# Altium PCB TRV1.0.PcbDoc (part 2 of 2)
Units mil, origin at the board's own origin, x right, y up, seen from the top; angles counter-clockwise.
Board outline 1659.57 x 2276.55 mil, 2 copper layers (Top Layer, Bottom Layer); 70 components, 42 nets, 217 pads, 204 vias.

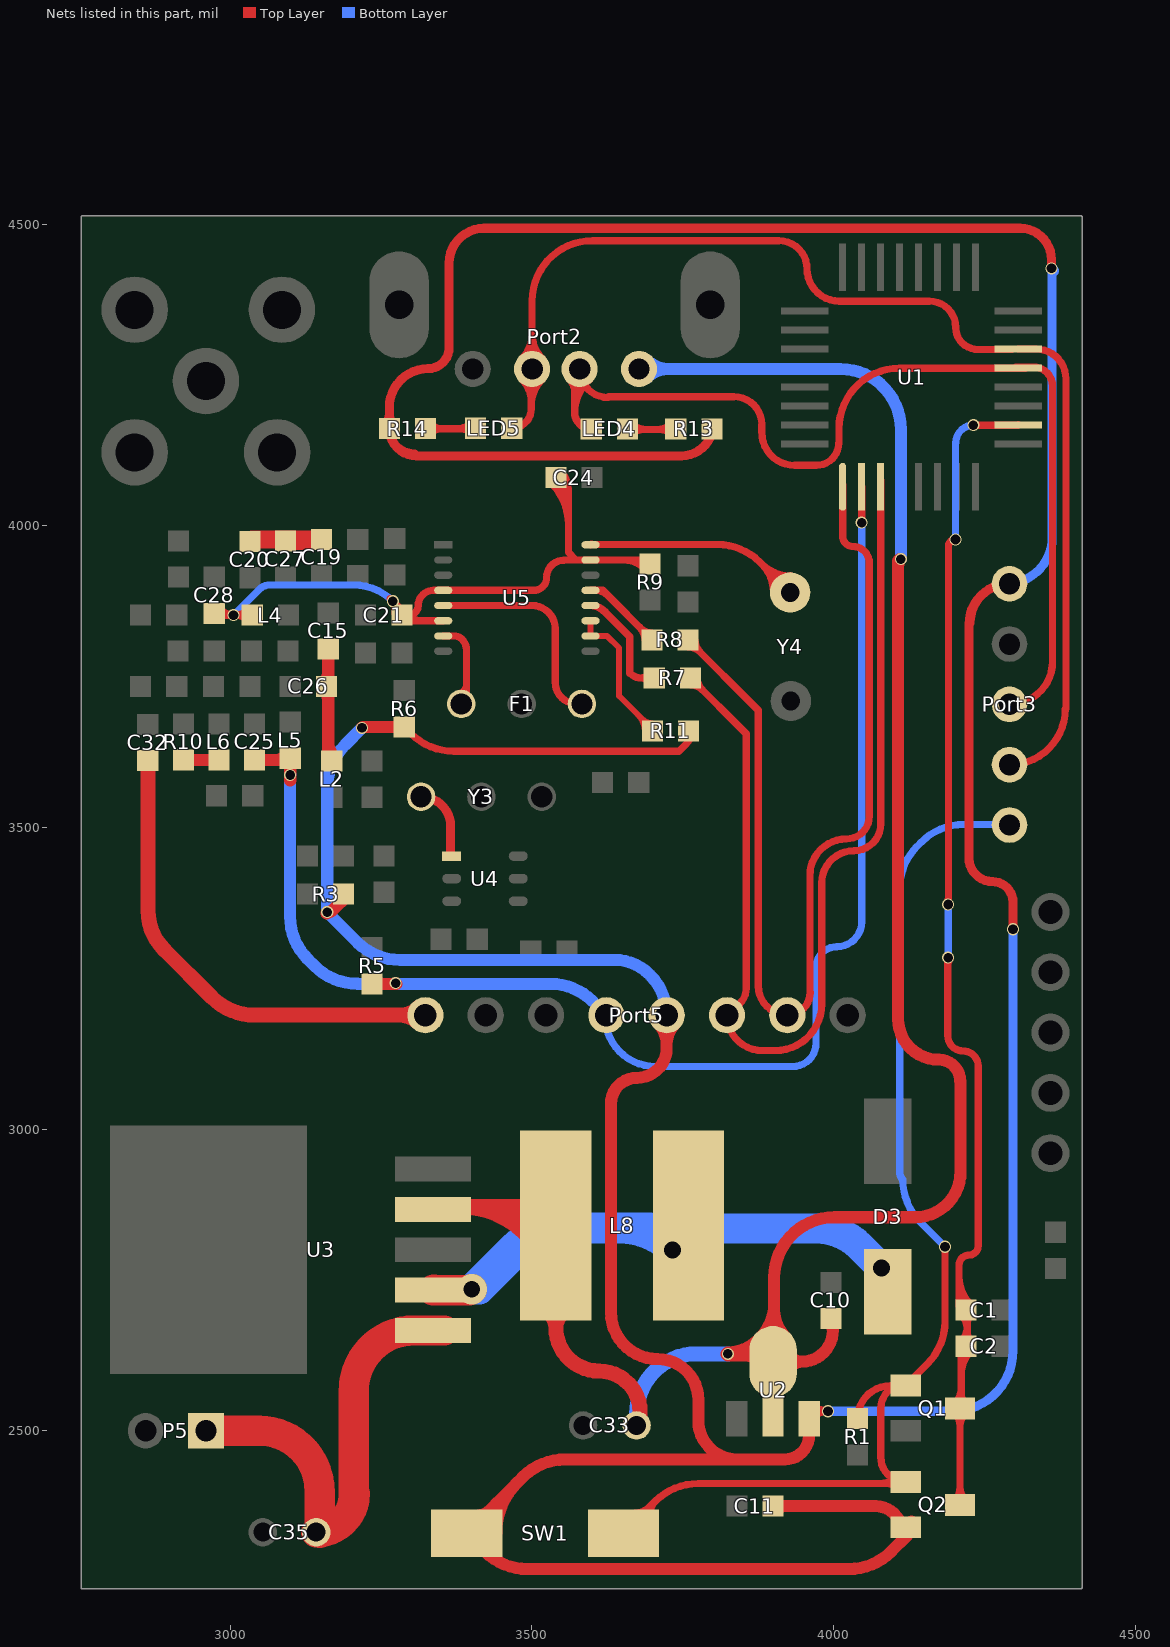
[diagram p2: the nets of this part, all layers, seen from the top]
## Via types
v1: diameter 20, hole 16, Top Layer to Bottom Layer, 201 vias
v2: diameter 50, hole 28, Top Layer to Bottom Layer, 3 vias

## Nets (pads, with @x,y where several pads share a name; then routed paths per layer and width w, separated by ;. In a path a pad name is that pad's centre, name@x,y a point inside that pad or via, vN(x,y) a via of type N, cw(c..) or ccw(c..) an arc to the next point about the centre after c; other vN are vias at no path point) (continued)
NetC32_2: C32.2 Port5.1 | length 997.3
  Top Layer w25: C32.2@2864.92,3607.21 ccw(c2859.9,3607.21) C32.2@2863.45,3610.76 cw(c2861.99,3609.3) 2864.06,3609.3 2864.06,3362.05 ccw(c2955.64,3362.05) 2890.88,3297.29 2970.09,3218.08 ccw(c3040.8,3288.79) 3040.8,3188.79 Port5.1@3323.69,3188.79 ; 3281.44,3188.79 ccw(c3281.44,3231.04) Port5.1@3311.32,3201.17 ; 3281.44,3188.79 cw(c3281.44,3146.54) Port5.1@3311.32,3176.42 ; 3281.44,3188.79 ccw(c3281.44,3231.04) Port5.1@3311.32,3201.17 ; 3281.44,3188.79 cw(c3281.44,3146.54) Port5.1@3311.32,3176.42 ; 3281.44,3188.79 ccw(c3281.44,3231.04) Port5.1@3311.32,3201.17 ; 3281.44,3188.79 cw(c3281.44,3146.54) Port5.1@3311.32,3176.42
NetC35_1: C35.1 P5.1 U3.1 | length 893.4
  Top Layer w50: P5.1@2960,2500 3048.39,2500 cw(c3048.39,2400) 3148.39,2400 cw(c3148.39,2399.87) 3148.52,2399.87 C35.1@3148.52,2332 ; C35.1@3148.52,2330.28 C35.1@3148.52,2331.99 ; 3207.04,2396.02 cw(c3142.76,2396.02) C35.1@3148.52,2331.99 ; U3.1@3354.95,2666.33 3305.08,2666.33 ccw(c3305.08,2566.33) 3205.08,2566.33 3205.08,2394.06 cw(c3142.76,2394.06) C35.1@3148.52,2332 ; C35.1@3148.52,2331.99 cw(c3142.76,2396.02) C35.1@3142.76,2331.73 ccw(c3142.76,2394.06) C35.1@3148.52,2332
NetD3_2: D3.2 L8.1 U3.2 | length 1406.9
  Top Layer w50: U3.2@3336.49,2732.96 cw(c3336.49,2733.34) U3.2@3336.22,2733.07 cw(c3338.37,2730.92) 3338.37,2733.96 ccw(c3340.8,2736.39) 3340.8,2732.96 3396.97,2732.96 cw(c3400.61,2729.32) v2(3400.61,2734.47) ; v2(3733.07,2799.49) cw(c3725.34,2791.77) L8.1@3736.27,2791.77 ; v2(3733.07,2799.49) cw(c3725.34,2791.77) L8.1@3736.27,2791.77 ; v2(3733.07,2799.49) cw(c3725.34,2791.77) L8.1@3736.27,2791.77
  Bottom Layer w50: 3647.13,2835.09 cw(c3647.13,2713.55) v2(3733.07,2799.49) ; 3819.01,2835.09 ccw(c3819.01,2713.55) v2(3733.07,2799.49) ; v2(4079.59,2769.9) 4043.69,2805.8 ccw(c3972.98,2735.09) 3972.98,2835.09 3894.69,2835.09 3544.33,2835.09 ccw(c3544.33,2831.04) 3541.47,2833.9 ccw(c3541.47,2733.9) 3470.76,2804.61 v2(3400.61,2734.47) 3413.06,2734.47 3485.81,2807.22 cw(c3556.52,2736.51) 3556.52,2836.51 3696.05,2836.51 v2(3733.07,2799.49)
NetF1_1: F1.1 U5.7 | length 203
  Top Layer w12: U5.7@3353.33,3817.41 3371.88,3817.41 cw(c3371.88,3799.96) 3384.22,3812.3 cw(c3365.71,3793.79) 3391.89,3793.79 3391.89,3736.01 ; F1.1@3383.25,3704.82 ccw(c3362.41,3725.66) 3391.89,3725.66 3391.89,3736.01 ; F1.1@3380.25,3722.18 ccw(c3377.86,3736.01) 3391.89,3736.01 ; F1.1@3380.25,3722.18 ccw(c3377.86,3736.01) 3391.89,3736.01 ; F1.1@3380.25,3722.18 ccw(c3377.86,3736.01) 3391.89,3736.01
NetF1_3: F1.3 U5.5 | length 361.1
  Top Layer w12: U5.5@3353.33,3867.81 3500.55,3867.81 cw(c3500.55,3829.39) 3538.96,3829.39 ccw(c3538.96,3829.31) 3538.88,3829.31 3538.88,3740.91 ccw(c3574.98,3740.91) 3574.98,3704.82 F1.3@3583.25,3704.82
NetL6_1: L6.1 R10.1 | length 229.7
  Top Layer w20: R10.1@2922.51,3611.71 L6.1@2981.56,3611.71 ; R10.1@2927.81,3606.4 cw(c2940.61,3593.6) 2940.61,3611.71 ; R10.1@2927.81,3606.4 cw(c2940.61,3593.6) 2940.61,3611.71 ; R10.1@2927.81,3606.4 cw(c2940.61,3593.6) 2940.61,3611.71 ; R10.1@2927.81,3617.01 ccw(c2940.61,3629.81) 2940.61,3611.71 ; R10.1@2927.81,3617.01 ccw(c2940.61,3629.81) 2940.61,3611.71 ; R10.1@2927.81,3617.01 ccw(c2940.61,3629.81) 2940.61,3611.71 ; 2963.45,3611.71 ccw(c2963.45,3629.81) L6.1@2976.26,3617.01 ; 2963.45,3611.71 cw(c2963.45,3593.6) L6.1@2976.26,3606.4 ; 2963.45,3611.71 ccw(c2963.45,3629.81) L6.1@2976.26,3617.01 ; 2963.45,3611.71 cw(c2963.45,3593.6) L6.1@2976.26,3606.4 ; 2963.45,3611.71 ccw(c2963.45,3629.81) L6.1@2976.26,3617.01 ; 2963.45,3611.71 cw(c2963.45,3593.6) L6.1@2976.26,3606.4
NetLED4_1: LED4.1 R13.1 | length 258.3
  Top Layer w12: R13.1@3740.63,4159.7 LED4.1@3659.61,4159.7 ; LED4.1@3659.61,4159.7 cw(c3659.61,4160.62) LED4.1@3658.7,4160.62 ccw(c3659.61,4160.62) LED4.1@3659.61,4159.7 ; LED4.1@3666.83,4152.49 cw(c3684.24,4135.08) 3684.24,4159.7 ccw(c3684.24,4135.08) LED4.1@3666.83,4152.49 ; LED4.1@3666.83,4168.75 ccw(c3688.68,4190.61) 3688.68,4159.7 cw(c3688.68,4190.61) LED4.1@3666.83,4168.75 ; 3708.71,4159.7 ccw(c3708.71,4190.61) 3730.56,4168.75 cw(c3708.71,4190.61) 3708.71,4159.7 ; 3713.15,4159.7 cw(c3713.15,4135.08) 3730.56,4152.49 ccw(c3713.15,4135.08) 3713.15,4159.7
NetLED5_1: LED5.1 R14.1 | length 186.4
  Top Layer w12: R14.1@3331.21,4163.99 ccw(c3331.21,4153.79) R14.1@3324,4161 ; R14.1@3332.13,4152.87 cw(c3351.69,4133.31) 3351.69,4160.97 ; R14.1@3332.13,4169.13 ccw(c3351.84,4188.84) 3351.84,4160.97 ; R14.1@3332.42,4164.49 ccw(c3332.42,4152.58) R14.1@3324,4161 ; 3377.08,4160.97 ccw(c3377.08,4191.65) LED5.1@3398.78,4169.96 ; 3381.21,4160.97 cw(c3381.21,4136.13) LED5.1@3398.78,4153.69 ; LED5.1@3405.48,4160.97 R14.1@3324.07,4160.97 ; R14.1@3324,4161 ccw(c3324.08,4161) 3324.08,4160.92 cw(c3324.08,4161) R14.1@3324,4161 ; R14.1@3324,4161 ccw(c3324.07,4161.07) R14.1@3324.07,4160.97 ; R14.1@3324,4161 ccw(c3324.07,4161.07) R14.1@3324.07,4160.97
NetR7_2: R7.2 U5.12 | length 306.3
  Top Layer w12: 3622.08,3857.6 ccw(c3597.43,3832.94) U5.12@3597.43,3867.81 cw(c3597.43,3837.77) 3618.67,3859.01 cw(c3618.67,3856.6) 3620.37,3858.3 3661.66,3817.02 cw(c3659.24,3814.6) 3662.66,3814.6 3662.66,3755.02 3663.66,3755.02 ccw(c3680.98,3772.34) 3680.98,3747.85 ; R7.2@3701.66,3747.85 R7.2@3703.06,3747.85 3680.98,3747.85 ; 3680.98,3747.85 ccw(c3680.98,3763.3) R7.2@3693.64,3754.44 ; 3680.98,3747.85 cw(c3680.98,3732.39) R7.2@3693.64,3741.25 ; 3680.98,3747.85 ccw(c3680.98,3763.3) R7.2@3693.64,3754.44 ; 3680.98,3747.85 cw(c3680.98,3732.39) R7.2@3693.64,3741.25 ; 3680.98,3747.85 ccw(c3680.98,3763.3) R7.2@3693.64,3754.44 ; 3680.98,3747.85 cw(c3680.98,3732.39) R7.2@3693.64,3741.25
NetR8_2: R8.2 U5.13 | length 386.2
  Top Layer w12: U5.13@3597.43,3893 3617.67,3893 3699.12,3811.55 R8.2@3699.12,3810.84 ; U5.13@3606.43,3893 cw(c3606.43,3865.86) 3625.62,3885.05 ; U5.13@3606.43,3893 cw(c3609.24,3873.33) 3623.29,3887.38 ; U5.13@3606.43,3893 cw(c3606.43,3865.86) 3625.62,3885.05 ; U5.13@3606.43,3893 cw(c3609.24,3873.33) 3623.29,3887.38 ; U5.13@3606.43,3893 cw(c3606.43,3865.86) 3625.62,3885.05 ; U5.13@3606.43,3893 cw(c3609.24,3873.33) 3623.29,3887.38 ; 3678.98,3831.69 cw(c3658.13,3810.84) R8.2@3687.62,3810.84 ; 3678.98,3831.69 cw(c3658.13,3810.84) R8.2@3687.62,3810.84 ; 3678.98,3831.69 cw(c3658.13,3810.84) R8.2@3687.62,3810.84 ; 3680.71,3829.96 ccw(c3699.12,3848.37) R8.2@3699.12,3822.34 ; 3680.71,3829.96 ccw(c3699.12,3848.37) R8.2@3699.12,3822.34 ; 3680.71,3829.96 ccw(c3699.12,3848.37) R8.2@3699.12,3822.34
NetR11_1: R11.1 U5.10 U5.11 | length 386.5
  Top Layer w10: U5.11@3597.43,3842.61 3597.43,3817.69 3624.66,3817.69 3644.66,3797.69 3644.66,3718.35 3696.91,3666.1 R11.1@3696.91,3655.47 ; 3676.54,3686.47 cw(c3650.07,3660) R11.1@3687.5,3660 ; 3676.54,3686.47 cw(c3650.07,3660) R11.1@3687.5,3660 ; 3676.54,3686.47 cw(c3650.07,3660) R11.1@3687.5,3660 ; 3683.79,3679.21 ccw(c3700,3695.43) R11.1@3700,3672.5 ; 3683.79,3679.21 ccw(c3700,3695.43) R11.1@3700,3672.5 ; 3683.79,3679.21 ccw(c3700,3695.43) R11.1@3700,3672.5
Netu4_1: U4.1 Y3.3 | length 390.7
  Top Layer w15: U4.1@3365.66,3452.02 U4.1@3365.66,3454.3 ; Y3.3@3316.6,3551 cw(c3316.6,3501.94) 3365.66,3501.94 ; Y3.3@3316.6,3551 cw(c3316.6,3501.94) 3365.66,3501.94 ; Y3.3@3316.6,3551 cw(c3316.6,3501.94) 3365.66,3501.94 ; Y3.3@3316.6,3551 cw(c3316.6,3501.94) 3365.66,3501.94 ; U4.1@3365.66,3454.3 ccw(c3367.39,3454.3) U4.1@3367.39,3452.57 ; U4.1@3365.66,3454.3 ccw(c3367.39,3454.3) U4.1@3367.39,3452.57 ; U4.1@3365.66,3454.3 ccw(c3367.39,3454.3) U4.1@3367.39,3452.57 ; U4.1@3365.66,3454.3 ccw(c3367.39,3454.3) U4.1@3367.39,3452.57 ; U4.1@3365.66,3454.3 ccw(c3367.39,3454.3) U4.1@3367.39,3452.57 ; U4.1@3365.66,3454.3 ccw(c3367.39,3454.3) U4.1@3367.39,3452.57 ; U4.1@3365.66,3454.3 ccw(c3367.39,3454.3) U4.1@3367.39,3452.57 ; U4.1@3365.66,3454.3 ccw(c3367.39,3454.3) U4.1@3367.39,3452.57 ; U4.1@3365.66,3454.3 ccw(c3367.39,3454.3) U4.1@3367.39,3452.57 ; U4.1@3365.66,3454.3 ccw(c3367.39,3454.3) U4.1@3367.39,3452.57 ; U4.1@3365.66,3454.3 3365.66,3501.94
  Top Layer w30: Y3.3@3316.6,3551 Y3.3@3320.38,3547.21
NetU5_16: U5.16 Y4.1 | length 855
  Top Layer w12: U5.16@3593.2,3969.03 U5.16@3597.96,3969.03 ; U5.16@3597.43,3968.6 cw(c3599.97,3966.06) U5.16@3597.96,3969.03 ; U5.16@3599.97,3969.65 ccw(c3599.97,3966.06) U5.16@3597.96,3969.03 ; Y4.1@3928.41,3889.58 3878.25,3939.74 ccw(c3807.54,3869.03) 3807.54,3969.03 U5.16@3597.96,3969.03 ; 3881.53,3936.46 ccw(c3928.41,3983.35) Y4.1@3928.41,3917.04 ; 3881.53,3936.46 cw(c3834.64,3889.58) Y4.1@3900.95,3889.58 ; 3881.53,3936.46 ccw(c3928.41,3983.35) Y4.1@3928.41,3917.04 ; 3881.53,3936.46 cw(c3834.64,3889.58) Y4.1@3900.95,3889.58 ; 3881.53,3936.46 ccw(c3928.41,3983.35) Y4.1@3928.41,3917.04 ; 3881.53,3936.46 cw(c3834.64,3889.58) Y4.1@3900.95,3889.58 ; 3902.01,3915.98 ccw(c3928.41,3942.38) Y4.1@3928.41,3905.04 ; 3902.01,3915.98 cw(c3875.61,3889.58) Y4.1@3912.95,3889.58 ; 3902.01,3915.98 ccw(c3928.41,3942.38) Y4.1@3928.41,3905.04 ; 3902.01,3915.98 cw(c3875.61,3889.58) Y4.1@3912.95,3889.58 ; 3902.01,3915.98 ccw(c3928.41,3942.38) Y4.1@3928.41,3905.04 ; 3902.01,3915.98 cw(c3875.61,3889.58) Y4.1@3912.95,3889.58
RFRXD: Port5.7 R8.1 U1.1 | length 2081.8
  Top Layer w12: R8.1@3759.12,3810.84 3875.66,3694.3 ; 3875.66,3482.02 3875.66,3694.3 ; Port5.7@3923.52,3189.53 cw(c3923.52,3237.39) 3875.66,3237.39 3875.66,3694.3 ; 3961.69,3226.79 cw(c3923.69,3226.79) Port5.7@3923.69,3188.79 ccw(c3923.69,3226.17) 3961.06,3226.17 3961.06,3420.23 cw(c4021.86,3420.23) 4021.86,3481.03 ccw(c4021.86,3518.84) 4059.67,3518.84 4059.67,3532.76 4059.67,3931.53 4059.67,3938.55 ccw(c4032.56,3938.55) 4032.56,3965.66 cw(c4032.56,3982.81) 4015.41,3982.81 U1.1@4015.41,4068.04 ; R8.1@3759.12,3799.34 cw(c3759.12,3771.57) 3778.75,3791.21 ; R8.1@3759.12,3799.34 cw(c3759.12,3771.57) 3778.75,3791.21 ; R8.1@3759.12,3799.34 cw(c3759.12,3771.57) 3778.75,3791.21 ; R8.1@3770.62,3810.84 ccw(c3798.39,3810.84) 3778.75,3791.21 ; R8.1@3770.62,3810.84 ccw(c3798.39,3810.84) 3778.75,3791.21 ; R8.1@3770.62,3810.84 ccw(c3798.39,3810.84) 3778.75,3791.21
RFTXD: C25.1 L5.2 Port5.4 R5.1 U1.2 | length 2661.9
  Top Layer w12: v1(4046.93,4005.14) U1.2@4046.93,4064.57
  Top Layer w20: C25.1@3040.62,3611.71 3071.88,3611.71 3096.68,3611.71 L5.2@3099.67,3614.7 3099.67,3578 cw(c3099.05,3578) 3099.49,3577.56 v1(3099.49,3586.97) ; R5.1@3235.5,3240.79 3275.66,3240.79 v1(3274.43,3242.02) ; C25.1@3045.92,3606.4 cw(c3058.72,3593.6) 3058.72,3611.71 ; C25.1@3045.92,3606.4 cw(c3058.72,3593.6) 3058.72,3611.71 ; C25.1@3045.92,3606.4 cw(c3058.72,3593.6) 3058.72,3611.71 ; C25.1@3045.92,3617.01 ccw(c3058.72,3629.81) 3058.72,3611.71 ; C25.1@3045.92,3617.01 ccw(c3058.72,3629.81) 3058.72,3611.71 ; C25.1@3045.92,3617.01 ccw(c3058.72,3629.81) 3058.72,3611.71 ; 3074.34,3611.71 ccw(c3074.34,3640.03) L5.2@3094.37,3620 ; 3074.34,3611.71 ccw(c3074.34,3640.03) L5.2@3094.37,3620 ; 3074.34,3611.71 ccw(c3074.34,3640.03) L5.2@3094.37,3620 ; L5.2@3094.37,3609.39 cw(c3081.57,3596.59) v1@3099.67,3596.59 ; L5.2@3094.37,3609.39 cw(c3081.57,3596.59) v1@3099.67,3596.59 ; L5.2@3094.37,3609.39 cw(c3081.57,3596.59) v1@3099.67,3596.59 ; v1@3099.67,3596.59 cw(c3117.78,3596.59) L5.2@3104.98,3609.39 ; v1@3099.67,3596.59 cw(c3117.78,3596.59) L5.2@3104.98,3609.39 ; v1@3099.67,3596.59 cw(c3117.78,3596.59) L5.2@3104.98,3609.39 ; R5.1@3240.8,3235.49 cw(c3253.61,3222.68) 3253.61,3240.79 ; R5.1@3240.8,3235.49 cw(c3253.61,3222.68) 3253.61,3240.79 ; R5.1@3240.8,3235.49 cw(c3253.61,3222.68) 3253.61,3240.79 ; R5.1@3240.8,3246.09 ccw(c3253.61,3258.9) 3253.61,3240.79 ; R5.1@3240.8,3246.09 ccw(c3253.61,3258.9) 3253.61,3240.79 ; R5.1@3240.8,3246.09 ccw(c3253.61,3258.9) 3253.61,3240.79
  Bottom Layer w12: Port5.4@3621.6,3187.01 ccw(c3704.77,3187.01) 3704.77,3103.84 3932.8,3103.84 ccw(c3932.8,3142.22) 3971.19,3142.22 3971.19,3267.84 cw(c4005.57,3267.84) 4005.57,3302.22 ccw(c4005.57,3343.58) 4046.93,3343.58 v1(4046.93,4005.14) ccw(c4047.05,4005.14) v1@4047.05,4005.02
  Bottom Layer w20: v1@3099.79,3587.7 ccw(c3100.52,3586.97) v1(3099.49,3586.97) 3099.49,3352.36 ccw(c3199.49,3352.36) 3128.78,3281.65 3140.13,3270.29 ccw(c3210.84,3341) 3210.84,3241 ccw(c3211.36,3241.52) 3211.36,3240.79 3235.66,3240.79 3531.28,3240.79 cw(c3531.28,3143.23) 3600.26,3212.22
RX: C19.1 C20.1 C27.2 | length 183.9
  Top Layer w30: C20.1@3035.02,3974.86 ccw(c3035.02,3971.63) 3032.75,3973.92 3036.36,3977.53 C19.1@3151.64,3977.53 3148.96,3974.86 C27.2@3091.8,3974.86
RXCE: Port5.6 R7.1 U1.3 | length 1944.1
  Top Layer w12: R7.1@3763.06,3747.85 3855.66,3655.25 3855.66,3441.75 ; Port5.6@3818.9,3197.15 ccw(c3818.9,3233.9) 3855.66,3233.9 3855.66,3441.75 ; Port5.6@3820.22,3185.32 Port5.6@3823.69,3188.79 ccw(c3882.39,3188.79) 3882.39,3130.09 3903.38,3130.09 ccw(c3903.38,3207.4) 3980.69,3207.4 3980.69,3408 cw(c4034.1,3408) 4034.1,3461.4 ccw(c4034.1,3505.98) 4078.67,3505.98 U1.3@4078.67,4075.47 ; 3855.66,3402.02 3855.66,3441.75 ; R7.1@3763.06,3736.35 cw(c3763.06,3708.58) 3782.69,3728.21 ; R7.1@3763.06,3736.35 cw(c3763.06,3708.58) 3782.69,3728.21 ; R7.1@3763.06,3736.35 cw(c3763.06,3708.58) 3782.69,3728.21 ; R7.1@3774.56,3747.85 ccw(c3802.32,3747.85) 3782.69,3728.21 ; R7.1@3774.56,3747.85 ccw(c3802.32,3747.85) 3782.69,3728.21 ; R7.1@3774.56,3747.85 ccw(c3802.32,3747.85) 3782.69,3728.21
RXD: LED4.2 Port2.2 Port3.3 U1.13 | length 2277.7
  Top Layer w12: 3570.74,4188.58 ccw(c3598.7,4188.58) LED4.2@3598.7,4160.62 ; Port2.2@3573.23,4266.19 3573.23,4265.78 cw(c3572.4,4265.78) 3572.4,4264.95 3571.16,4264.95 3571.16,4188.16 ccw(c3598.7,4188.16) LED4.2@3598.7,4160.62 ; U1.13@4302.48,4263.27 4331.64,4263.27 cw(c4331.64,4231.6) 4363.31,4231.6 4363.31,3775.31 ; U1.13@4318.61,4261.2 4109.3,4261.2 ccw(c4109.3,4161.2) 4009.3,4161.2 4009.3,4137.48 cw(c4008.82,4137.48) 4008.82,4137 cw(c3972.12,4137) 3972.12,4100.31 3936.18,4100.31 ccw(c3936.18,4100.05) 3935.93,4100.05 cw(c3935.93,4154.52) 3881.47,4154.52 3881.47,4167.76 ccw(c3835.11,4167.76) 3835.11,4214.13 3628.18,4214.13 ccw(c3628.18,4212.66) 3626.71,4212.66 ; LED4.2@3598.7,4160.62 cw(c3598.7,4187.75) 3571.57,4187.75 ccw(c3598.7,4187.75) LED4.2@3598.7,4160.62 ; 3626.71,4212.66 cw(c3626.71,4260) Port2.2@3579.37,4260 ccw(c3626.71,4260) 3626.71,4212.66 ; 4363.31,3775.31 cw(c4292,3775.31) Port3.3@4292,3704 ccw(c4292,3775.31) 4363.31,3775.31 ; Port2.2@3562.4,4243.03 cw(c3541.26,4221.89) 3571.15,4221.89 ccw(c3541.26,4221.89) Port2.2@3562.4,4243.03 ; 3571.16,4187.7 cw(c3644.4,4187.7) 3595.42,4242.16 ccw(c3644.4,4187.7) 3571.16,4187.7 ; 3571.15,4214.63 cw(c3620.18,4214.63) 3587.39,4251.08 ccw(c3620.18,4214.63) 3571.15,4214.63
TRG: Port3.5 Q1.2 Q2.2 R1.2 SW1.2 | length 2421.2
  Top Layer w12: SW1.2@3651.98,2330.26 3704.75,2383.04 ; SW1.2@3671.66,2363.63 ccw(c3671.66,2396.67) 3695.02,2373.31 ; SW1.2@3690.01,2341.21 cw(c3711.79,2354.21) 3693.86,2372.14 ; SW1.2@3700.32,2347.36 cw(c3725.44,2362.35) 3704.75,2383.04 ; 4077.58,2412.33 ccw(c4077.58,2450.42) Q2.2@4104.51,2423.49 ; 4090.48,2412.33 cw(c4090.48,2392.48) Q2.2@4104.51,2406.51 ; Q2.2@4105.14,2412.33 3775.47,2412.33 ccw(c3775.47,2312.33) 3704.75,2383.04 ; Q1.2@4119.48,2577.51 ccw(c4119.48,2536.72) 4078.7,2536.72 4078.7,2456.3 ccw(c4120,2456.3) Q2.2@4120,2415 ; Q1.2@4120,2575 4155.71,2610.71 ccw(c4085,2681.42) 4185,2681.42 v1(4185,2805) ; R1.2@4040,2520 cw(c4094.49,2520) 4094.49,2574.49 ; R1.2@4040,2520 cw(c4094.49,2520) 4094.49,2574.49 ; R1.2@4040,2520 cw(c4094.49,2520) 4094.49,2574.49 ; R1.2@4040,2520 cw(c4094.49,2520) 4094.49,2574.49 ; Q2.2@4120,2415 cw(c4120,2456.68) 4078.32,2456.68 ccw(c4120,2456.68) Q2.2@4120,2415
  Bottom Layer w12: v1(4185,2805) 4144.29,2845.71 cw(c4215,2916.42) 4115,2916.42 cw(c4127.07,2928.49) 4110,2928.49 4110,3398.58 cw(c4210,3398.58) 4139.29,3469.29 4145.71,3475.71 cw(c4216.42,3405) 4216.42,3505 Port3.5@4290,3505
TX: C15.2 C26.2 L2.1 | length 497.2
  Top Layer w20: C15.2@3162.66,3795.8 3162.66,3615.96 L2.1@3168.57,3610.05 ; C26.2@3154.37,3728.45 cw(c3134.34,3708.42) 3162.66,3708.42 ; C26.2@3154.37,3728.45 cw(c3134.34,3708.42) 3162.66,3708.42 ; C26.2@3154.37,3728.45 cw(c3134.34,3708.42) 3162.66,3708.42 ; C26.2@3154.37,3739.06 ccw(c3134.34,3759.08) 3162.66,3759.08 ; C26.2@3154.37,3739.06 ccw(c3134.34,3759.08) 3162.66,3759.08 ; C26.2@3154.37,3739.06 ccw(c3134.34,3759.08) 3162.66,3759.08 ; C15.2@3157.36,3790.5 cw(c3144.56,3777.69) 3162.66,3777.69 ; C15.2@3157.36,3790.5 cw(c3144.56,3777.69) 3162.66,3777.69 ; C15.2@3157.36,3790.5 cw(c3144.56,3777.69) 3162.66,3777.69 ; 3162.66,3642.42 ccw(c3200.94,3642.42) L2.1@3173.87,3615.35 ; 3162.66,3642.42 ccw(c3200.94,3642.42) L2.1@3173.87,3615.35 ; 3162.66,3642.42 ccw(c3200.94,3642.42) L2.1@3173.87,3615.35 ; 3162.66,3777.69 cw(c3180.77,3777.69) C15.2@3167.97,3790.5 ; 3162.66,3777.69 cw(c3180.77,3777.69) C15.2@3167.97,3790.5 ; 3162.66,3777.69 cw(c3180.77,3777.69) C15.2@3167.97,3790.5
TXD: LED5.2 Port2.3 Port3.4 U1.14 | length 2606
  Top Layer w12: LED5.2@3467.39,4161.82 LED5.2@3466.91,4161.82 ; Port2.3@3499.28,4266.19 3499.28,4194.2 ; Port2.3@3500.49,4260 Port2.3@3500.49,4261.41 ; Port2.3@3500.63,4260 3500.63,4372.72 cw(c3600.63,4372.72) 3600.63,4472.72 3909.48,4472.72 cw(c3909.48,4425.88) 3956.33,4425.88 ccw(c4009.76,4425.88) 4009.76,4372.45 4038.1,4372.45 4159.39,4372.45 cw(c4159.39,4329.09) 4202.74,4329.09 ccw(c4239.48,4329.09) 4239.48,4292.35 U1.14@4295.79,4292.35 ; U1.14@4306,4292.93 4336.16,4292.93 cw(c4336.16,4243.67) 4385.43,4243.67 4385.43,3697.43 cw(c4384.42,3697.43) 4384.42,3696.42 ; LED5.2@3466.91,4161.82 ccw(c3466.91,4194.2) LED5.2@3467.39,4161.83 ; LED5.2@3466.91,4161.82 ccw(c3466.91,4194.2) LED5.2@3467.39,4161.83 ; LED5.2@3467.39,4161.83 ccw(c3466.91,4194.2) 3499.28,4194.2 ; LED5.2@3467.39,4161.83 ccw(c3466.91,4194.2) 3499.28,4194.2 ; 3500.63,4317.94 ccw(c3558.57,4317.94) 3517.6,4276.97 cw(c3558.57,4317.94) 3500.63,4317.94 ; 3500.63,4317.94 cw(c3442.69,4317.94) 3483.66,4276.97 ccw(c3442.69,4317.94) 3500.63,4317.94 ; 4384.42,3696.42 cw(c4292,3696.42) Port3.4@4292,3604 ccw(c4292,3696.42) 4384.42,3696.42 ; Port2.3@3483.66,4243.03 cw(c3445.94,4205.31) 3499.28,4205.31 ccw(c3445.94,4205.31) Port2.3@3483.66,4243.03 ; 3499.28,4198.81 cw(c3561.82,4198.81) 3517.6,4243.03 ccw(c3561.82,4198.81) 3499.28,4198.81 ; 3499.28,4227.78 cw(c3532.85,4227.78) 3509.12,4251.51 ccw(c3532.85,4227.78) 3499.28,4227.78
V2: C21.1 C24.2 C28.2 L4.1 R9.1 U5.4 U5.6 U5.15 | length 2784.1
  Top Layer w12: C28.2@2973.69,3854.86 2976.68,3851.86 L4.1@3036.68,3851.86 3036.52,3852.02 v1(3005.66,3852.02) ; v1(3269.71,3874.97) 3284.71,3859.97 C21.1@3284.71,3851.86 ; U5.6@3353.33,3842.61 3316.28,3842.61 ; C24.2@3537.11,4081.7 3560.81,4057.99 3560.81,3956.16 3573.57,3943.4 ; R9.1@3689.55,3943.4 U5.15@3597.43,3943.4 3573.57,3943.4 ; C28.2@2981.82,3846.72 cw(c2994.23,3834.32) 2994.23,3851.86 ; C28.2@2981.82,3846.72 cw(c2994.23,3834.32) 2994.23,3851.86 ; C28.2@2981.82,3846.72 cw(c2994.23,3834.32) 2994.23,3851.86 ; C28.2@2981.82,3862.99 ccw(c3008.67,3889.84) v1@3008.67,3851.86 ; C28.2@2981.82,3862.99 ccw(c3008.67,3889.84) v1@3008.67,3851.86 ; C28.2@2981.82,3862.99 ccw(c3008.67,3889.84) v1@3008.67,3851.86 ; 2995.63,3851.86 ccw(c2995.63,3862.05) v1@3002.83,3854.85 ; 2995.63,3851.86 ccw(c2995.63,3862.05) v1@3002.83,3854.85 ; 2995.63,3851.86 ccw(c2995.63,3862.05) v1@3002.83,3854.85 ; v1@3008.49,3854.85 ccw(c3015.69,3862.05) 3015.69,3851.86 ; v1@3008.49,3854.85 ccw(c3015.69,3862.05) 3015.69,3851.86 ; v1@3008.49,3854.85 ccw(c3015.69,3862.05) 3015.69,3851.86 ; v1@3008.54,3852.02 cw(c3008.54,3823.72) L4.1@3028.55,3843.73 ; v1@3008.54,3852.02 cw(c3008.54,3823.72) L4.1@3028.55,3843.73 ; v1@3008.54,3852.02 cw(c3008.54,3823.72) L4.1@3028.55,3843.73 ; v1@3008.92,3851.86 ccw(c3008.92,3879.63) L4.1@3028.55,3860 ; v1@3008.92,3851.86 cw(c3008.92,3824.1) L4.1@3028.55,3843.73 ; v1@3008.92,3851.86 ccw(c3008.92,3879.63) L4.1@3028.55,3860 ; v1@3008.92,3851.86 cw(c3008.92,3824.1) L4.1@3028.55,3843.73 ; v1@3008.92,3851.86 ccw(c3008.92,3879.63) L4.1@3028.55,3860 ; v1@3008.92,3851.86 cw(c3008.92,3824.1) L4.1@3028.55,3843.73 ; v1@3009.29,3852.02 ccw(c3009.29,3879.25) L4.1@3028.55,3860 ; v1@3009.29,3852.02 ccw(c3009.29,3879.25) L4.1@3028.55,3860 ; v1@3009.29,3852.02 ccw(c3009.29,3879.25) L4.1@3028.55,3860 ; v1@3265.66,3879.02 cw(c3245.8,3859.15) C21.1@3273.41,3853.98 ; v1@3265.66,3879.02 cw(c3245.8,3859.15) C21.1@3273.41,3853.98 ; v1@3265.66,3879.02 cw(c3245.8,3859.15) C21.1@3273.41,3853.98 ; C21.1@3284.71,3851.86 ccw(c3293.96,3851.86) 3293.96,3842.61 3316.28,3842.61 ; C21.1@3284.71,3851.86 3296.11,3851.86 ccw(c3296.11,3867.46) 3311.71,3867.46 cw(c3337.26,3867.46) 3337.26,3893 U5.4@3353.33,3893 3503.5,3893 ccw(c3503.5,3914.16) 3524.66,3914.16 3524.66,3914.47 cw(c3553.19,3914.47) 3553.19,3943 cw(c3553.59,3943) 3553.59,3943.4 3573.57,3943.4 ; C21.1@3295.27,3856.42 ccw(c3316.28,3865.5) 3316.28,3842.61 ; C21.1@3295.27,3856.42 ccw(c3316.28,3865.5) 3316.28,3842.61 ; C21.1@3295.27,3856.42 ccw(c3316.28,3865.5) 3316.28,3842.61 ; C24.2@3531.87,4071.87 cw(c3462.01,4002.01) 3560.81,4002.01 ; C24.2@3531.87,4071.87 cw(c3462.01,4002.01) 3560.81,4002.01 ; C24.2@3531.87,4071.87 cw(c3462.01,4002.01) 3560.81,4002.01 ; C24.2@3540,4068.5 cw(c3540,4043.63) 3557.58,4061.22 ; C24.2@3540,4068.5 cw(c3540,4043.63) 3557.58,4061.22 ; C24.2@3540,4068.5 cw(c3540,4043.63) 3557.58,4061.22 ; C24.2@3540.35,4080.35 cw(c3490.98,4030.98) 3560.81,4030.98 ; C24.2@3540.35,4080.35 cw(c3490.98,4030.98) 3560.81,4030.98 ; C24.2@3540.35,4080.35 cw(c3490.98,4030.98) 3560.81,4030.98 ; C24.2@3548.84,4088.84 cw(c3519.95,4059.95) 3560.81,4059.95 ; C24.2@3548.84,4088.84 cw(c3519.95,4059.95) 3560.81,4059.95 ; C24.2@3548.84,4088.84 cw(c3519.95,4059.95) 3560.81,4059.95 ; C24.2@3551.5,4079.89 ccw(c3581.23,4079.62) 3560.21,4058.6 ; C24.2@3551.5,4079.89 ccw(c3581.23,4079.62) 3560.21,4058.6 ; C24.2@3551.5,4079.89 ccw(c3581.23,4079.62) 3560.21,4058.6 ; 3652.49,3943.4 cw(c3652.49,3893.18) R9.1@3688,3928.69 ; 3652.49,3943.4 cw(c3652.49,3893.18) R9.1@3688,3928.69 ; 3652.49,3943.4 cw(c3652.49,3893.18) R9.1@3688,3928.69
  Bottom Layer w12: v1@3009.68,3852.02 v1(3005.66,3852.02) 3048.59,3894.95 cw(c3065.66,3877.88) 3065.66,3902.02 3204.4,3902.02 ; 3085.66,3902.02 3204.4,3902.02 ; 3204.4,3902.02 cw(c3204.4,3809.65) v1(3269.71,3874.97) ; 3204.4,3902.02 cw(c3204.4,3809.65) v1(3269.71,3874.97) ; 3204.4,3902.02 cw(c3204.4,3809.65) v1(3269.71,3874.97) ; 3204.4,3902.02 cw(c3204.4,3809.65) v1(3269.71,3874.97)
V5: C10.1 C33.1 L8.2 Port2.1 U2.2 U3.4 | length 4435.8
  Top Layer w20: U2.2@3900,2614.49 U2.2@3901.86,2614.49 ; U2.2@3901.86,2586.24 U2.2@3901.86,2614.49 ; U2.2@3926.27,2601.35 cw(c3947.54,2590.7) 3947.54,2614.49 ; U2.2@3926.27,2627.63 ccw(c3947.54,2638.28) 3947.54,2614.49 ; C10.1@3991.8,2679.79 cw(c3982.4,2665.9) 3999.17,2665.9 ; C10.1@3999.17,2687.48 3999.17,2666.15 cw(c3947.48,2666.15) 3984.03,2629.6 cw(c3947.54,2666.09) 3947.54,2614.49 ; v1@4110.31,3943.24 cw(c4111.87,3943.24) v1(4111.87,3944.8) ; 4210.22,3079.79 ccw(c4174.96,3079.79) 4174.96,3115.06 cw(c4174.96,3182.65) 4107.37,3182.65 4107.37,3940.3 cw(c4111.87,3940.3) v1(4111.87,3944.8) ; 4210.24,3079.78 cw(c4210.24,3079.17) 4210.85,3079.17 4210.85,2929.29 cw(c4135.43,2929.29) 4135.43,2853.86 4001.86,2853.86 ccw(c4001.86,2753.86) 3901.86,2753.86 U2.2@3901.86,2614.49 ; U2.2@3901.86,2614.49 3947.54,2614.49 ; v1(4111.87,3944.8) ccw(c4122.74,3933.93) 4107.37,3933.93 cw(c4122.74,3933.93) v1(4111.87,3944.8) ; U2.2@3879.23,2654.94 ccw(c3824.6,2709.58) 3901.86,2709.58 cw(c3824.6,2709.58) U2.2@3879.23,2654.94 ; 3901.86,2700.58 ccw(c3966.41,2700.58) 3920.77,2654.94 cw(c3966.41,2700.58) 3901.86,2700.58
  Top Layer w25: U3.4@3384.32,2861.15 cw(c3409.43,2836.05) 3409.43,2871.55 ; 3430.54,2871.55 cw(c3430.54,2753.75) L8.2@3523.07,2826.66 ; L8.2@3482.07,2871.55 cw(c3482.07,2794.35) L8.2@3542.71,2842.13 ; L8.2@3503.43,2811.19 ccw(c3379.02,2713.15) 3379.02,2871.55 3542.84,2871.55 ccw(c3546.07,2871.55) L8.2@3546.07,2868.32 ; L8.2@3521.51,2698.85 cw(c3509.32,2670.7) 3540,2670.7 ; L8.2@3540,2840 3540,2670.69 ; L8.2@3558.49,2698.85 ccw(c3570.68,2670.7) 3540,2670.7 ; C33.1@3679.65,2508.41 3679.65,2531.04 ccw(c3611.77,2531.04) 3611.77,2598.92 cw(c3611.77,2670.69) 3540,2670.69 ; 3851.13,2627.55 cw(c3851.13,2585.3) U2.2@3881,2615.17 ; U2.2@3879.95,2652.06 cw(c3825.21,2700.91) v1(3825.21,2627.55) U2.2@3893.34,2627.55 ; U3.4@3336.22,2866.93 cw(c3339.77,2866.93) U3.4@3339.77,2870.47 ; U3.4@3336.22,2866.93 cw(c3339.77,2866.93) U3.4@3339.77,2870.47 ; U3.4@3336.22,2866.93 cw(c3339.77,2866.93) U3.4@3339.77,2870.47 ; U3.4@3336.22,2866.93 cw(c3339.77,2866.93) U3.4@3339.77,2870.47 ; U3.4@3336.22,2866.93 cw(c3339.77,2866.93) U3.4@3339.77,2870.47 ; U3.4@3336.22,2866.93 cw(c3339.77,2866.93) U3.4@3339.77,2870.47 ; U3.4@3336.22,2866.93 cw(c3339.77,2866.93) U3.4@3339.77,2870.47 ; U3.4@3336.22,2866.93 cw(c3339.77,2866.93) U3.4@3339.77,2870.47
  Bottom Layer w20: Port2.1@3691.67,4246.12 cw(c3691.67,4260) Port2.1@3677.8,4260 4011.87,4260 cw(c4011.87,4160) 4111.87,4160 v1(4111.87,3944.8) ; 3726.08,4260 ccw(c3726.08,4211.72) 3691.94,4245.86 cw(c3726.08,4211.72) 3726.08,4260 ; 3726.08,4260 cw(c3726.08,4308.28) 3691.94,4274.14 ccw(c3726.08,4308.28) 3726.08,4260
  Bottom Layer w25: C33.1@3673.76,2508.73 3673.76,2527.55 cw(c3773.76,2527.55) 3773.76,2627.55 v1(3825.21,2627.55)
VCC: C11.1 Port3.1 Port5.5 Q2.1 R3.1 R6.1 R11.2 R13.2 R14.2 SW1.1 U2.3 | length 9286.2
  Top Layer w12: R6.1@3288.65,3666.82 3299.85,3655.62 ccw(c3370.56,3726.34) 3370.56,3626.34 3744.16,3626.34 3756.01,3638.19 ccw(c3735.83,3658.37) R11.2@3764.37,3658.37
  Top Layer w15: 3305.62,4119.38 cw(c3305.62,4161) R14.2@3264,4161 ; R13.2@3800.91,4168.89 cw(c3748.05,4168.89) 3748.05,4116.03 3308.97,4116.03 cw(c3308.97,4161) R14.2@3264,4161 ; U2.3@3965.17,2533.08 v1@3990.26,2533.08 ; 4226.56,3838.56 cw(c4292,3838.56) Port3.1@4292,3904 ccw(c4292,3836.74) 4224.74,3836.74 4224.74,3449.25 ccw(c4263.66,3449.25) 4263.66,3410.32 cw(c4263.66,3376.26) 4297.73,3376.26 v1(4297.73,3331.25) ; v1(4361.62,4426.87) 4361.62,4441.25 ccw(c4309.65,4441.25) 4309.65,4493.22 3421.07,4493.22 ccw(c3421.07,4435.16) 3363.01,4435.16 3363.01,4295.27 cw(c3328.17,4295.27) 3328.17,4260.43 ccw(c3328.17,4196.26) 3264,4196.26 R14.2@3264,4161 ; 3264,4185.14 ccw(c3288.14,4185.14) 3271.07,4168.07 cw(c3288.14,4185.14) 3264,4185.14 ; 3264,4185.14 cw(c3239.86,4185.14) 3256.93,4168.07 ccw(c3239.86,4185.14) 3264,4185.14 ; v1@3990.26,2533.08 cw(c3990.26,2532.27) v1(3991.07,2532.27) ccw(c3990.26,2532.27) v1@3990.26,2533.08 ; U2.3@3967.22,2524.59 cw(c3987.72,2504.09) 3987.72,2533.08 ccw(c3987.72,2504.09) U2.3@3967.22,2524.59 ; U2.3@3967.22,2539.04 ccw(c3981.61,2553.42) 3981.61,2533.08 cw(c3981.61,2553.42) U2.3@3967.22,2539.04
  Top Layer w20: v1@3160.22,3357.61 cw(c3162.99,3357.61) v1(3161.03,3359.57) ; R3.1@3192.88,3385.68 3170.81,3363.62 ; v1@3218.83,3665.35 cw(c3222.37,3661.81) 3222.37,3666.82 R6.1@3288.65,3666.82 ; SW1.1@3411.82,2359.63 ccw(c3411.82,2383.01) SW1.1@3428.35,2366.48 ; SW1.1@3421.19,2330.26 cw(c3491.33,2330.26) 3441.73,2379.86 ; SW1.1@3441.19,2330.26 cw(c3559.62,2330.26) 3475.88,2414 ; Port5.5@3709.55,3174.65 cw(c3675.41,3140.51) 3723.69,3140.51 cw(c3771.97,3140.51) Port5.5@3737.83,3174.65 ; Port5.5@3723.69,3188.79 3723.69,3134.25 cw(c3674.31,3134.25) 3674.31,3084.87 ccw(c3674.31,3041.85) 3631.29,3041.85 3631.29,2696.22 ccw(c3708.73,2696.22) 3708.73,2618.77 cw(c3708.73,2551.37) 3776.14,2551.37 3776.14,2516.95 ccw(c3840.59,2516.95) 3840.59,2452.5 3919.55,2452.5 ccw(c3919.55,2492.66) 3959.71,2492.66 U2.3@3959.71,2538.46 ; 3879.85,2452.4 3555.69,2452.4 ccw(c3555.69,2352.4) 3484.98,2423.11 SW1.1@3392.13,2330.26 3422.36,2300.03 ccw(c3493.08,2370.74) 3493.08,2270.74 4016.98,2270.74 4025.43,2270.74 ccw(c4025.43,2370.74) 4096.14,2300.03 4122.06,2325.95 ccw(c4104.86,2343.15) 4129.19,2343.15 Q2.1@4129.19,2349.1 ; C11.1@3900,2375 4070.24,2375 cw(c4070.24,2331.52) Q2.1@4113.72,2331.52 ; C11.1@3905.3,2369.7 cw(c3918.11,2356.89) 3918.11,2375 cw(c3918.11,2393.11) C11.1@3905.3,2380.3 ; v1(3161.03,3359.57) ccw(c3161.03,3373.4) 3170.81,3363.62 ; v1(3161.03,3359.57) ccw(c3161.03,3373.4) 3170.81,3363.62 ; v1(3161.03,3359.57) ccw(c3161.03,3373.4) 3170.81,3363.62 ; 3270.54,3666.82 ccw(c3270.54,3684.93) 3283.34,3672.13 cw(c3270.54,3684.93) 3270.54,3666.82 ; 3270.54,3666.82 cw(c3270.54,3648.72) 3283.34,3661.52 ccw(c3270.54,3648.72) 3270.54,3666.82 ; 3175.07,3367.88 ccw(c3159.68,3383.27) 3180.93,3387.96 cw(c3159.68,3383.27) 3175.07,3367.88
  Bottom Layer w15: v1(3991.07,2532.27) 4197.73,2532.27 ccw(c4197.73,2632.27) 4297.73,2632.27 v1(4297.73,3331.25) ; Port3.1@4286.08,3904.05 ccw(c4286.08,3980.63) 4362.67,3980.63 4362.67,4425.83 ccw(c4361.62,4425.83) v1(4361.62,4426.87) cw(c4361.62,4421.99) v1@4366.5,4421.99
  Bottom Layer w20: v1(3218.74,3665.05) 3190.37,3636.67 ccw(c3261.08,3565.96) 3161.08,3565.96 3161.08,3359.61 v1(3161.03,3359.57) 3210.99,3309.6 ccw(c3281.71,3380.31) 3281.71,3280.31 cw(c3282.07,3279.94) 3282.07,3280.46 3636.99,3280.46 cw(c3636.99,3198.44) 3694.99,3256.44 3695.93,3255.49 cw(c3628.63,3188.19) Port5.5@3723.81,3188.19
VCORE: C1.2 C2.2 Q1.3 Q2.3 U1.10 | length 2578
  Top Layer w12: v1@4191.03,3370.13 4190.69,3370.13 4190.69,3400.98 4190.7,3965.65 ; Q2.3@4201.51,2385.49 ccw(c4181.03,2405.97) 4210,2405.97 ccw(c4238.97,2405.97) Q2.3@4218.49,2385.49 ; Q1.3@4201.51,2528.51 cw(c4181.03,2508.03) 4210,2508.03 cw(c4238.97,2508.03) Q1.3@4218.49,2528.51 ; Q1.3@4201.51,2545.49 ccw(c4176.42,2570.58) 4211.91,2570.58 ; C1.2@4208.35,2706.02 4208.35,2774.75 cw(c4224.77,2774.75) 4224.77,2791.17 ccw(c4224.77,2806.38) 4239.98,2806.38 4239.98,2883.01 ; Q1.3@4210,2537 4210,2369.14 ccw(c4212.6,2369.14) Q2.3@4212.6,2366.54 ; C2.2@4211.87,2648.13 ccw(c4187.73,2672.27) 4221.87,2672.27 ; C1.2@4211.87,2691.87 cw(c4187.73,2667.73) 4221.87,2667.73 ; Q1.3@4211.91,2537.17 4211.91,2629.53 cw(c4221.87,2629.53) 4221.87,2639.48 4221.87,2698.13 ccw(c4220,2698.13) C1.2@4220,2700 ; 4211.91,2561.36 ccw(c4234.36,2561.36) Q1.3@4218.49,2545.49 ; 4211.91,2592.71 cw(c4267.29,2592.71) C2.2@4228.13,2631.87 ; 4211.91,2621.68 cw(c4238.32,2621.68) C2.2@4219.65,2640.35 ; 4221.87,2663.26 ccw(c4243.26,2663.26) C2.2@4228.13,2648.13 ; 4221.87,2676.74 cw(c4243.26,2676.74) C1.2@4228.13,2691.87 ; v1(4232.02,4166.78) 4305.64,4166.78 ccw(c4305.64,4167) 4305.85,4167 ccw(c4305.85,4167.42) 4306.28,4167.42 cw(c4306.28,4166.93) U1.10@4306.77,4166.93 ccw(c4306.73,4166.93) U1.10@4306.73,4166.98 ; 4239.98,2813.07 4239.98,2883.01 ; v1@4189.66,3283.61 cw(c4190.35,3283.61) v1(4190.35,3284.3) ccw(c4190.35,3283.61) v1@4189.66,3283.61 ; v1@4189.66,3283.61 4189.66,3154.86 ccw(c4215.07,3154.86) 4215.07,3129.46 cw(c4215.07,3104.55) 4239.98,3104.55 4239.98,2883.01 ; 4190.7,3965.65 cw(c4202.41,3965.65) v1(4202.41,3977.36) ccw(c4202.41,3965.65) 4190.7,3965.65 ; C1.2@4220,2700 cw(c4220,2699.51) 4220.49,2699.51 ccw(c4220,2699.51) C1.2@4220,2700 ; v1@4187.52,3375.02 ccw(c4179.86,3382.68) 4190.69,3382.68 cw(c4179.86,3382.68) v1@4187.52,3375.02 ; 4189.66,3272.99 cw(c4201.66,3272.99) 4193.18,3281.47 ccw(c4201.66,3272.99) 4189.66,3272.99 ; 4208.35,2726.93 ccw(c4246.93,2726.93) 4219.65,2699.65 cw(c4246.93,2726.93) 4208.35,2726.93 ; 4208.35,2755.9 ccw(c4275.9,2755.9) 4228.13,2708.13 cw(c4275.9,2755.9) 4208.35,2755.9
  Bottom Layer w12: v1(4190.35,3284.3) v1(4190.35,3372.19) ; v1(4202.41,3977.36) 4202.41,4137.18 cw(c4203.02,4137.18) 4203.02,4137.79 ; 4203.02,4137.79 cw(c4232.02,4137.79) v1(4232.02,4166.78) ccw(c4232.02,4137.79) 4203.02,4137.79
pads on no net: P6.2 P6.4 P6.5 Port5.3 U1.6 U1.7 U1.8 U1.9 U1.11 U1.16 U1.17 U1.18 U1.19 U1.20 U1.21 U1.22 U1.23 U1.24 U1.25 U1.26 U1.27 U1.28 U1.29 U1.30 U1.31 U1.32 U3.6

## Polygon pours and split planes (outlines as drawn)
GND on Bottom Layer "Top Layer-No Net" (solid, remove dead copper, pour order 1000): 2610,4615 2559.29,4564.29 ccw(c2630,4493.58) 2530,4493.58 2530,1940 4732.93,1940 cw(c4732.93,1922.93) 4745,1935 4860.71,2050.71 ccw(c4790,2121.42) 4890,2121.42 4890,4660
GND on Top Layer "Top Layer-No Net" (solid, remove dead copper, pour order 1001): 2690,4605 2690,2199.14 ccw(c2724.14,2199.14) 2700,2175 cw(c2712.07,2162.93) 2712.07,2180 4625,2180 4625,4538.79 ccw(c4573.79,4538.79) 4610,4575

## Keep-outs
Keep-Out Layer:
  lines w6: 4409.45,2240.7 4409.45,4511.22 2755.91,4511.22 2755.91,2240.7 4409.28,2240.7 4409.45,2240.87

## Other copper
Top Layer:
  pour cut-out: 3315.66,3962.02 2855.66,3962.02 2855.66,3592.02 3155.66,3592.02 3145.66,3602.02 3145.66,3792.02 3315.66,3792.02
